VERSION 5.6 ;
BUSBITCHARS "[]" ;
DIVIDERCHAR "/" ;

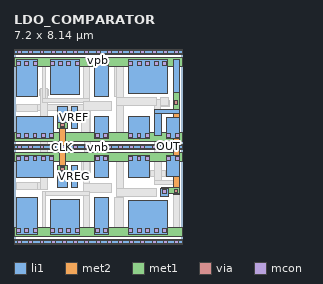
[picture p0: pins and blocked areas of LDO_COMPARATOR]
MACRO LDO_COMPARATOR
  CLASS CORE ;
  ORIGIN 0 0 ;
  FOREIGN LDO_COMPARATOR 0 0 ;
  SIZE 7.2 BY 8.14 ;
  SYMMETRY X Y ;
  SITE unithv ;
  PIN VREF
    DIRECTION INPUT ;
    USE SIGNAL ;
    PORT
      LAYER li1 ;
        RECT 2.455 4.88 2.725 5.795 ;
    END
  END VREF
  PIN VREG
    DIRECTION INOUT ;
    USE POWER ;
    PORT
      LAYER li1 ;
        RECT 2.455 2.345 2.725 3.26 ;
    END
  END VREG
  PIN OUT
    DIRECTION OUTPUT ;
    USE SIGNAL ;
    PORT
      LAYER met2 ;
        RECT 6.82 2.035 7.08 6.13 ;
      LAYER met1 ;
        RECT 6.315 2.065 7.11 2.325 ;
        RECT 6.82 5.63 7.08 6.385 ;
      LAYER li1 ;
        RECT 6.82 5.495 7.075 7.825 ;
        RECT 6 5.495 7.075 5.665 ;
        RECT 6 4.565 6.33 5.665 ;
        RECT 6.295 1.95 6.625 2.295 ;
      LAYER via ;
        RECT 6.875 5.895 7.025 6.045 ;
        RECT 6.875 2.12 7.025 2.27 ;
      LAYER mcon ;
        RECT 6.375 2.095 6.545 2.265 ;
        RECT 6.85 5.885 7.02 6.055 ;
    END
  END OUT
  PIN vgnd
    DIRECTION INOUT ;
    USE GROUND ;
    PORT
      LAYER met1 ;
        RECT 0 3.445 7.2 3.815 ;
        RECT 0 4.325 7.2 4.695 ;
      LAYER li1 ;
        RECT 6.52 2.825 7.11 3.705 ;
        RECT 6.52 4.435 7.11 5.315 ;
        RECT 4.89 2.745 5.82 3.705 ;
        RECT 4.89 4.435 5.82 5.395 ;
        RECT 3.45 2.745 4.04 3.705 ;
        RECT 3.45 4.435 4.04 5.395 ;
        RECT 0.09 2.745 1.705 3.705 ;
        RECT 0.09 4.435 1.705 5.395 ;
      LAYER mcon ;
        RECT 0.095 4.465 0.265 4.635 ;
        RECT 0.095 3.505 0.265 3.675 ;
        RECT 0.455 4.465 0.625 4.635 ;
        RECT 0.455 3.505 0.625 3.675 ;
        RECT 0.815 4.465 0.985 4.635 ;
        RECT 0.815 3.505 0.985 3.675 ;
        RECT 1.175 4.465 1.345 4.635 ;
        RECT 1.175 3.505 1.345 3.675 ;
        RECT 1.535 4.465 1.705 4.635 ;
        RECT 1.535 3.505 1.705 3.675 ;
        RECT 3.48 4.465 3.65 4.635 ;
        RECT 3.48 3.505 3.65 3.675 ;
        RECT 3.84 4.465 4.01 4.635 ;
        RECT 3.84 3.505 4.01 3.675 ;
        RECT 4.91 4.465 5.08 4.635 ;
        RECT 4.91 3.505 5.08 3.675 ;
        RECT 5.27 4.465 5.44 4.635 ;
        RECT 5.27 3.505 5.44 3.675 ;
        RECT 5.63 4.465 5.8 4.635 ;
        RECT 5.63 3.505 5.8 3.675 ;
        RECT 6.55 4.465 6.72 4.635 ;
        RECT 6.55 3.505 6.72 3.675 ;
        RECT 6.91 4.465 7.08 4.635 ;
        RECT 6.91 3.505 7.08 3.675 ;
    END
  END vgnd
  PIN vnb
    DIRECTION INOUT ;
    USE GROUND ;
    PORT
      LAYER met1 ;
        RECT 0 3.955 7.2 4.185 ;
      LAYER li1 ;
        RECT 0 3.985 7.2 4.155 ;
      LAYER mcon ;
        RECT 0.155 3.985 0.325 4.155 ;
        RECT 0.635 3.985 0.805 4.155 ;
        RECT 1.115 3.985 1.285 4.155 ;
        RECT 1.595 3.985 1.765 4.155 ;
        RECT 2.075 3.985 2.245 4.155 ;
        RECT 2.555 3.985 2.725 4.155 ;
        RECT 3.035 3.985 3.205 4.155 ;
        RECT 3.515 3.985 3.685 4.155 ;
        RECT 3.995 3.985 4.165 4.155 ;
        RECT 4.475 3.985 4.645 4.155 ;
        RECT 4.955 3.985 5.125 4.155 ;
        RECT 5.435 3.985 5.605 4.155 ;
        RECT 5.915 3.985 6.085 4.155 ;
        RECT 6.395 3.985 6.565 4.155 ;
        RECT 6.875 3.985 7.045 4.155 ;
    END
  END vnb
  PIN vpb
    DIRECTION INOUT ;
    USE POWER ;
    PORT
      LAYER met1 ;
        RECT 0 -0.115 7.2 0.115 ;
        RECT 0 8.025 7.2 8.255 ;
      LAYER li1 ;
        RECT 0 -0.085 7.2 0.085 ;
        RECT 0 8.055 7.2 8.225 ;
      LAYER mcon ;
        RECT 0.155 8.055 0.325 8.225 ;
        RECT 0.155 -0.085 0.325 0.085 ;
        RECT 0.635 8.055 0.805 8.225 ;
        RECT 0.635 -0.085 0.805 0.085 ;
        RECT 1.115 8.055 1.285 8.225 ;
        RECT 1.115 -0.085 1.285 0.085 ;
        RECT 1.595 8.055 1.765 8.225 ;
        RECT 1.595 -0.085 1.765 0.085 ;
        RECT 2.075 8.055 2.245 8.225 ;
        RECT 2.075 -0.085 2.245 0.085 ;
        RECT 2.555 8.055 2.725 8.225 ;
        RECT 2.555 -0.085 2.725 0.085 ;
        RECT 3.035 8.055 3.205 8.225 ;
        RECT 3.035 -0.085 3.205 0.085 ;
        RECT 3.515 8.055 3.685 8.225 ;
        RECT 3.515 -0.085 3.685 0.085 ;
        RECT 3.995 8.055 4.165 8.225 ;
        RECT 3.995 -0.085 4.165 0.085 ;
        RECT 4.475 8.055 4.645 8.225 ;
        RECT 4.475 -0.085 4.645 0.085 ;
        RECT 4.955 8.055 5.125 8.225 ;
        RECT 4.955 -0.085 5.125 0.085 ;
        RECT 5.435 8.055 5.605 8.225 ;
        RECT 5.435 -0.085 5.605 0.085 ;
        RECT 5.915 8.055 6.085 8.225 ;
        RECT 5.915 -0.085 6.085 0.085 ;
        RECT 6.395 8.055 6.565 8.225 ;
        RECT 6.395 -0.085 6.565 0.085 ;
        RECT 6.875 8.055 7.045 8.225 ;
        RECT 6.875 -0.085 7.045 0.085 ;
    END
  END vpb
  PIN vpwr
    DIRECTION INOUT ;
    USE POWER ;
    PORT
      LAYER met1 ;
        RECT 0 0.255 7.2 0.625 ;
        RECT 0 7.515 7.2 7.885 ;
      LAYER li1 ;
        RECT 4.89 0.315 6.56 1.77 ;
        RECT 4.89 6.37 6.56 7.825 ;
        RECT 3.45 0.315 4.04 1.895 ;
        RECT 3.45 6.245 4.04 7.825 ;
        RECT 1.55 0.315 2.8 1.815 ;
        RECT 1.55 6.325 2.8 7.825 ;
        RECT 0.09 0.315 1.02 1.895 ;
        RECT 0.09 6.245 1.02 7.825 ;
      LAYER mcon ;
        RECT 0.11 7.575 0.28 7.745 ;
        RECT 0.11 0.395 0.28 0.565 ;
        RECT 0.47 7.575 0.64 7.745 ;
        RECT 0.47 0.395 0.64 0.565 ;
        RECT 0.83 7.575 1 7.745 ;
        RECT 0.83 0.395 1 0.565 ;
        RECT 1.55 7.575 1.72 7.745 ;
        RECT 1.55 0.395 1.72 0.565 ;
        RECT 1.91 7.575 2.08 7.745 ;
        RECT 1.91 0.395 2.08 0.565 ;
        RECT 2.27 7.575 2.44 7.745 ;
        RECT 2.27 0.395 2.44 0.565 ;
        RECT 2.63 7.575 2.8 7.745 ;
        RECT 2.63 0.395 2.8 0.565 ;
        RECT 3.48 7.575 3.65 7.745 ;
        RECT 3.48 0.395 3.65 0.565 ;
        RECT 3.84 7.575 4.01 7.745 ;
        RECT 3.84 0.395 4.01 0.565 ;
        RECT 4.92 7.575 5.09 7.745 ;
        RECT 4.92 0.395 5.09 0.565 ;
        RECT 5.28 7.575 5.45 7.745 ;
        RECT 5.28 0.395 5.45 0.565 ;
        RECT 5.64 7.575 5.81 7.745 ;
        RECT 5.64 0.395 5.81 0.565 ;
        RECT 6 7.575 6.17 7.745 ;
        RECT 6 0.395 6.17 0.565 ;
        RECT 6.36 7.575 6.53 7.745 ;
        RECT 6.36 0.395 6.53 0.565 ;
    END
  END vpwr
  PIN CLK
    DIRECTION INPUT ;
    USE SIGNAL ;
    PORT
      LAYER met2 ;
        RECT 1.945 2.975 2.205 5.165 ;
      LAYER met1 ;
        RECT 1.885 3.005 2.275 3.265 ;
        RECT 1.855 4.875 2.275 5.135 ;
      LAYER li1 ;
        RECT 1.885 2.345 2.275 3.26 ;
        RECT 1.885 4.88 2.275 5.795 ;
      LAYER via ;
        RECT 2 4.93 2.15 5.08 ;
        RECT 2 3.06 2.15 3.21 ;
      LAYER mcon ;
        RECT 1.975 4.905 2.145 5.075 ;
        RECT 1.99 3.05 2.16 3.22 ;
    END
  END CLK
  OBS
    LAYER mcon ;
      RECT 6.425 5.845 6.595 6.015 ;
      RECT 6.08 2.855 6.25 3.025 ;
      RECT 3.03 3.03 3.2 3.2 ;
      RECT 1.2 6.325 1.37 6.495 ;
      RECT 0.745 2.315 0.915 2.485 ;
      RECT 0.745 5.655 0.915 5.825 ;
    LAYER met1 ;
      RECT 6.005 5.815 6.655 6.075 ;
      RECT 5.835 2.795 6.495 3.055 ;
      RECT 2.905 2.99 3.295 3.25 ;
      RECT 0.685 5.615 3.295 5.875 ;
      RECT 1.095 6.28 1.475 6.54 ;
      RECT 0.645 2.27 1.445 2.53 ;
    LAYER via ;
      RECT 6.09 2.85 6.24 3 ;
      RECT 6.09 5.87 6.24 6.02 ;
      RECT 3.06 3.045 3.21 3.195 ;
      RECT 3.06 5.67 3.21 5.82 ;
      RECT 1.21 2.325 1.36 2.475 ;
      RECT 1.21 6.335 1.36 6.485 ;
    LAYER met2 ;
      RECT 6.035 2.765 6.295 6.105 ;
      RECT 3.005 2.96 3.265 5.905 ;
      RECT 1.155 2.24 1.415 6.57 ;
    LAYER li1 ;
      RECT 6 2.475 6.33 3.575 ;
      RECT 6 2.475 7.075 2.645 ;
      RECT 6.82 0.315 7.075 2.645 ;
      RECT 4.375 0.315 4.705 3.575 ;
      RECT 4.375 1.95 6.115 2.295 ;
      RECT 4.32 0.315 4.705 1.895 ;
      RECT 4.32 6.245 4.705 7.825 ;
      RECT 4.375 4.565 4.705 7.825 ;
      RECT 4.375 5.845 6.115 6.19 ;
      RECT 2.905 2.745 3.235 3.575 ;
      RECT 2.98 0.315 3.235 3.575 ;
      RECT 2.98 2.135 4.195 2.52 ;
      RECT 1.2 1.995 3.235 2.165 ;
      RECT 1.2 0.315 1.37 2.165 ;
      RECT 2.98 4.565 3.235 7.825 ;
      RECT 1.2 5.975 1.37 7.825 ;
      RECT 1.2 5.975 3.235 6.145 ;
      RECT 2.98 5.62 4.195 6.005 ;
      RECT 2.905 4.565 3.235 5.395 ;
      RECT 6.295 5.845 6.625 6.19 ;
      RECT 0.125 2.235 0.995 2.565 ;
      RECT 0.125 5.575 0.995 5.905 ;
  END
END LDO_COMPARATOR

END LIBRARY
